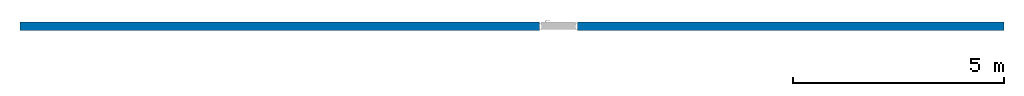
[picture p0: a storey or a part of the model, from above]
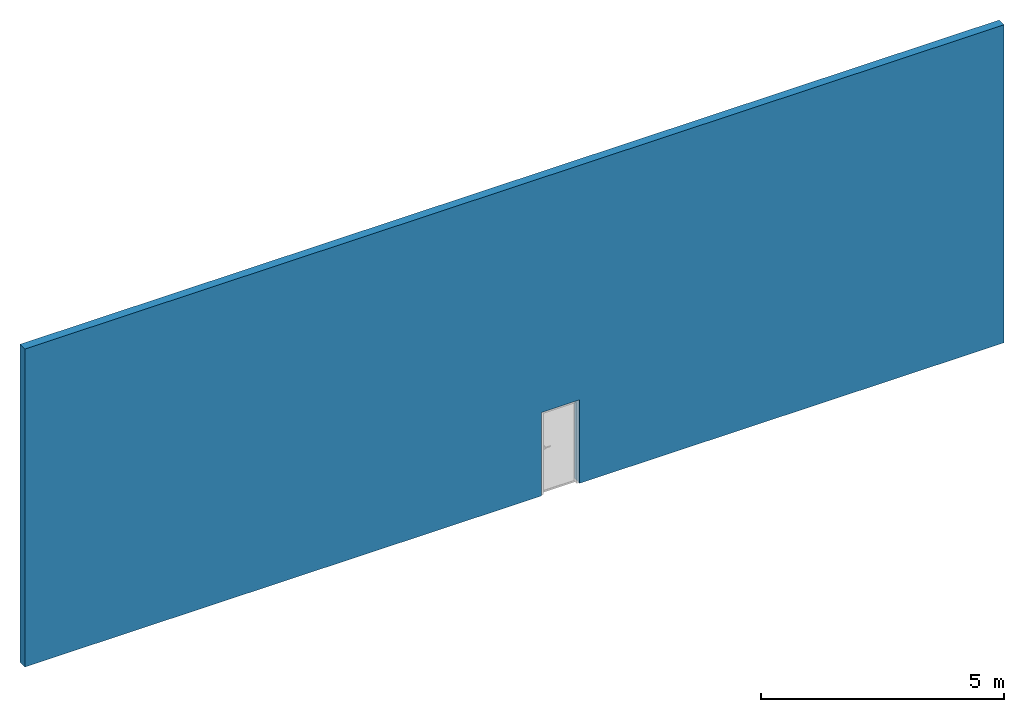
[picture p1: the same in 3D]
Properties of the parts of a building model (IFC2X3)

# File
Description: ViewDefinition [CoordinationView]
File name: Project Number
Time: 2016-06-12T10:09:47
Written by: Autodesk Revit Architecture 2011 - 1.0
Made in: 20100326_1700(x64)

# IfcProject, Project Number
LongName: Project Name; Phase: Project Status

# IfcSite, 默认
RefLatitude: 42, 12, 46, 800000; RefLongitude: -71, -1, -58, -800000; RefElevation: 0 mm

# IfcBuilding
Pset_BuildingCommon - NumberOfStoreys: 1
PSet_Revit_其他 - 项目发布日期: Issue Date; 项目状态: Project Status; 客户姓名: Owner; 项目地址: Enter address here; 项目名称: Project Name; 项目编号: Project Number

# IfcBuildingStorey, Level 1
Elevation: 0 mm
PSet_Revit_标识数据 - 名称: Level 1
PSet_Revit_限制条件 - 立面: 0 mm
PSet_Revit_Type_图形 - 线宽: 1; 颜色: 0; 线型图案: Centre; 符号: M_Level Head - Circle; 端点 1 处的默认符号: no; 端点 2 处的默认符号: yes
PSet_Revit_Type_限制条件 - 基面: 0
PSet_Revit_Type_尺寸标注 - 自动计算房间高度: no; 计算高度: 1200 mm

# IfcDoor: HUE010003, HUE010003:HUE010003:HUE010003:109911
In: Level 1
Type - ParameterTakesPrecedence: no; Sizeable: no
OverallHeight: 2100 mm; OverallWidth: 900 mm
Pset_DoorCommon - Reference: HUE010003:HUE010003; IsExternal: yes
PSet_Revit_限制条件 - 标高: Level 1; 底高度: 0 mm
PSet_Revit_其他 - 顶高度: 2100 mm
PSet_Revit_标识数据 - 标记: 1
PSet_Revit_阶段化 - 创建的阶段: New Construction
PSet_Revit_Type_标识数据 - URL: www.huet.fr; Tél.: 00 33 (0)2 28 12 04 20; 类型注释: Fabriquant de Menuiseries Exterieures, HUET vous offre une large gamme de Fenetres et Porte-Fenetres permettant d’appréhender les différents segments de marché.; 型号: Axiome BP1; 制造商: Huet; Fax: 02 51 49 19 00; 说明: Huisserie bois ou métal; Adresse: 30 rue Pauline de Lezardière 85300 Challans; 类型标记: 33
PSet_Revit_Type_材质和装饰 - Remplissage: Huet RAL 9016; Metal: Huet gris anodisé; Cadre: Huet Sablé
PSet_Revit_Type_构造 - 功能: 0; 墙闭合: 0
PSet_Revit_Type_其他 - START: 370 mm; Height of lock: 1059.52 mm; H1: 1050 mm; END: 450 mm; NUMBER: 5; Frame Projection Ext.: 25 mm; Frame Projection Int.: 25 mm; Frame Width: 75 mm; Actual Width: 900 mm; Actual Height: 2100 mm
PSet_Revit_Type_限制条件 - Minimal Width: 800 mm; Minimal Height: 400 mm; Maximal Width: 6000 mm; Maximal Height: 6000 mm
PSet_Revit_Type_尺寸标注 - 高度: 2100 mm; 宽度: 900 mm

# IfcWallStandardCase: 基本墙:Generic - 200mm:398, 基本墙:Generic - 200mm:107942
In: Level 1
Material: Default Wall 200 mm
Pset_WallCommon - Reference: 基本墙:Generic - 200mm; LoadBearing: no; ExtendToStructure: no; IsExternal: yes
PSet_Revit_限制条件 - 定位线: 0; 基准限制条件: Level 1; 底部偏移: 0 mm; 已附着底部: no; 底部延伸距离: 0 mm; 无连接高度: 8000 mm; 顶部偏移: 0 mm; 已附着顶部: no; 顶部延伸距离: 0 mm; 房间边界: yes; 与体量相关: no
PSet_Revit_阶段化 - 创建的阶段: New Construction
PSet_Revit_结构 - 结构用途: 0
PSet_Revit_尺寸标注 - 长度: 23300 mm; 面积: 184510000 mm2; 体积: 36902000000 mm3
PSet_Revit_Type_构造 - 在插入点包络: 0; 在端点包络: 0; 宽度: 200 mm; 功能: 1
PSet_Revit_Type_图形 - 粗略比例填充颜色: 0
